VERSION 5.7 ;
  NOWIREEXTENSIONATPIN ON ;
  DIVIDERCHAR "/" ;
  BUSBITCHARS "[]" ;
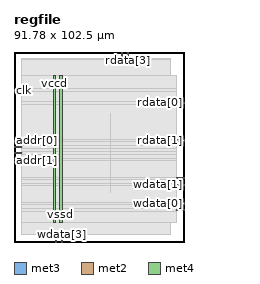
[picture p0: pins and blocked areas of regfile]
MACRO regfile
  CLASS BLOCK ;
  FOREIGN regfile ;
  ORIGIN 0.000 0.000 ;
  SIZE 91.780 BY 102.500 ;
  PIN addr[0]
    DIRECTION INPUT ;
    USE SIGNAL ;
    ANTENNAGATEAREA 0.196500 ;
    PORT
      LAYER met3 ;
        RECT 0.000 54.440 4.000 55.040 ;
    END
  END addr[0]
  PIN addr[1]
    DIRECTION INPUT ;
    USE SIGNAL ;
    ANTENNAGATEAREA 0.196500 ;
    PORT
      LAYER met3 ;
        RECT 0.000 47.640 4.000 48.240 ;
    END
  END addr[1]
  PIN addr[2]
    DIRECTION INPUT ;
    USE SIGNAL ;
    ANTENNAGATEAREA 0.196500 ;
    PORT
      LAYER met3 ;
        RECT 0.000 44.240 4.000 44.840 ;
    END
  END addr[2]
  PIN addr[3]
    DIRECTION INPUT ;
    USE SIGNAL ;
    ANTENNAGATEAREA 0.196500 ;
    PORT
      LAYER met3 ;
        RECT 0.000 51.040 4.000 51.640 ;
    END
  END addr[3]
  PIN clk
    DIRECTION INPUT ;
    USE SIGNAL ;
    ANTENNAGATEAREA 0.196500 ;
    PORT
      LAYER met3 ;
        RECT 0.000 81.640 4.000 82.240 ;
    END
  END clk
  PIN nrst
    DIRECTION INPUT ;
    USE SIGNAL ;
    ANTENNAGATEAREA 0.196500 ;
    PORT
      LAYER met3 ;
        RECT 87.780 17.040 91.780 17.640 ;
    END
  END nrst
  PIN rdata[0]
    DIRECTION OUTPUT ;
    USE SIGNAL ;
    ANTENNADIFFAREA 0.445500 ;
    PORT
      LAYER met3 ;
        RECT 87.780 74.840 91.780 75.440 ;
    END
  END rdata[0]
  PIN rdata[1]
    DIRECTION OUTPUT ;
    USE SIGNAL ;
    ANTENNADIFFAREA 0.445500 ;
    PORT
      LAYER met3 ;
        RECT 87.780 54.440 91.780 55.040 ;
    END
  END rdata[1]
  PIN rdata[2]
    DIRECTION OUTPUT ;
    USE SIGNAL ;
    ANTENNADIFFAREA 0.445500 ;
    PORT
      LAYER met2 ;
        RECT 58.050 98.500 58.330 102.500 ;
    END
  END rdata[2]
  PIN rdata[3]
    DIRECTION OUTPUT ;
    USE SIGNAL ;
    ANTENNADIFFAREA 0.445500 ;
    PORT
      LAYER met2 ;
        RECT 61.270 98.500 61.550 102.500 ;
    END
  END rdata[3]
  PIN vccd
    DIRECTION INOUT ;
    USE POWER ;
    PORT
      LAYER met4 ;
        RECT 21.040 10.640 22.640 90.000 ;
    END
  END vccd
  PIN vssd
    DIRECTION INOUT ;
    USE GROUND ;
    PORT
      LAYER met4 ;
        RECT 24.340 10.640 25.940 90.000 ;
    END
  END vssd
  PIN wdata[0]
    DIRECTION INPUT ;
    USE SIGNAL ;
    ANTENNAGATEAREA 0.196500 ;
    PORT
      LAYER met3 ;
        RECT 87.780 20.440 91.780 21.040 ;
    END
  END wdata[0]
  PIN wdata[1]
    DIRECTION INPUT ;
    USE SIGNAL ;
    ANTENNAGATEAREA 0.196500 ;
    PORT
      LAYER met3 ;
        RECT 87.780 30.640 91.780 31.240 ;
    END
  END wdata[1]
  PIN wdata[2]
    DIRECTION INPUT ;
    USE SIGNAL ;
    ANTENNAGATEAREA 0.196500 ;
    PORT
      LAYER met2 ;
        RECT 22.630 0.000 22.910 4.000 ;
    END
  END wdata[2]
  PIN wdata[3]
    DIRECTION INPUT ;
    USE SIGNAL ;
    ANTENNAGATEAREA 0.196500 ;
    PORT
      LAYER met2 ;
        RECT 25.850 0.000 26.130 4.000 ;
    END
  END wdata[3]
  PIN we
    DIRECTION INPUT ;
    USE SIGNAL ;
    ANTENNAGATEAREA 0.196500 ;
    PORT
      LAYER met3 ;
        RECT 87.780 34.040 91.780 34.640 ;
    END
  END we
  OBS
      LAYER nwell ;
        RECT 5.330 10.795 86.210 89.950 ;
      LAYER li1 ;
        RECT 5.520 10.795 86.020 89.845 ;
      LAYER met1 ;
        RECT 4.210 10.640 86.020 90.000 ;
      LAYER met2 ;
        RECT 4.230 98.220 57.770 99.010 ;
        RECT 58.610 98.220 60.990 99.010 ;
        RECT 61.830 98.220 84.550 99.010 ;
        RECT 4.230 4.280 84.550 98.220 ;
        RECT 4.230 4.000 22.350 4.280 ;
        RECT 23.190 4.000 25.570 4.280 ;
        RECT 26.410 4.000 84.550 4.280 ;
      LAYER met3 ;
        RECT 3.990 82.640 87.780 89.925 ;
        RECT 4.400 81.240 87.780 82.640 ;
        RECT 3.990 75.840 87.780 81.240 ;
        RECT 3.990 74.440 87.380 75.840 ;
        RECT 3.990 55.440 87.780 74.440 ;
        RECT 4.400 54.040 87.380 55.440 ;
        RECT 3.990 52.040 87.780 54.040 ;
        RECT 4.400 50.640 87.780 52.040 ;
        RECT 3.990 48.640 87.780 50.640 ;
        RECT 4.400 47.240 87.780 48.640 ;
        RECT 3.990 45.240 87.780 47.240 ;
        RECT 4.400 43.840 87.780 45.240 ;
        RECT 3.990 35.040 87.780 43.840 ;
        RECT 3.990 33.640 87.380 35.040 ;
        RECT 3.990 31.640 87.780 33.640 ;
        RECT 3.990 30.240 87.380 31.640 ;
        RECT 3.990 21.440 87.780 30.240 ;
        RECT 3.990 20.040 87.380 21.440 ;
        RECT 3.990 18.040 87.780 20.040 ;
        RECT 3.990 16.640 87.380 18.040 ;
        RECT 3.990 10.715 87.780 16.640 ;
      LAYER met4 ;
        RECT 51.815 26.695 52.145 69.185 ;
  END
END regfile
END LIBRARY

